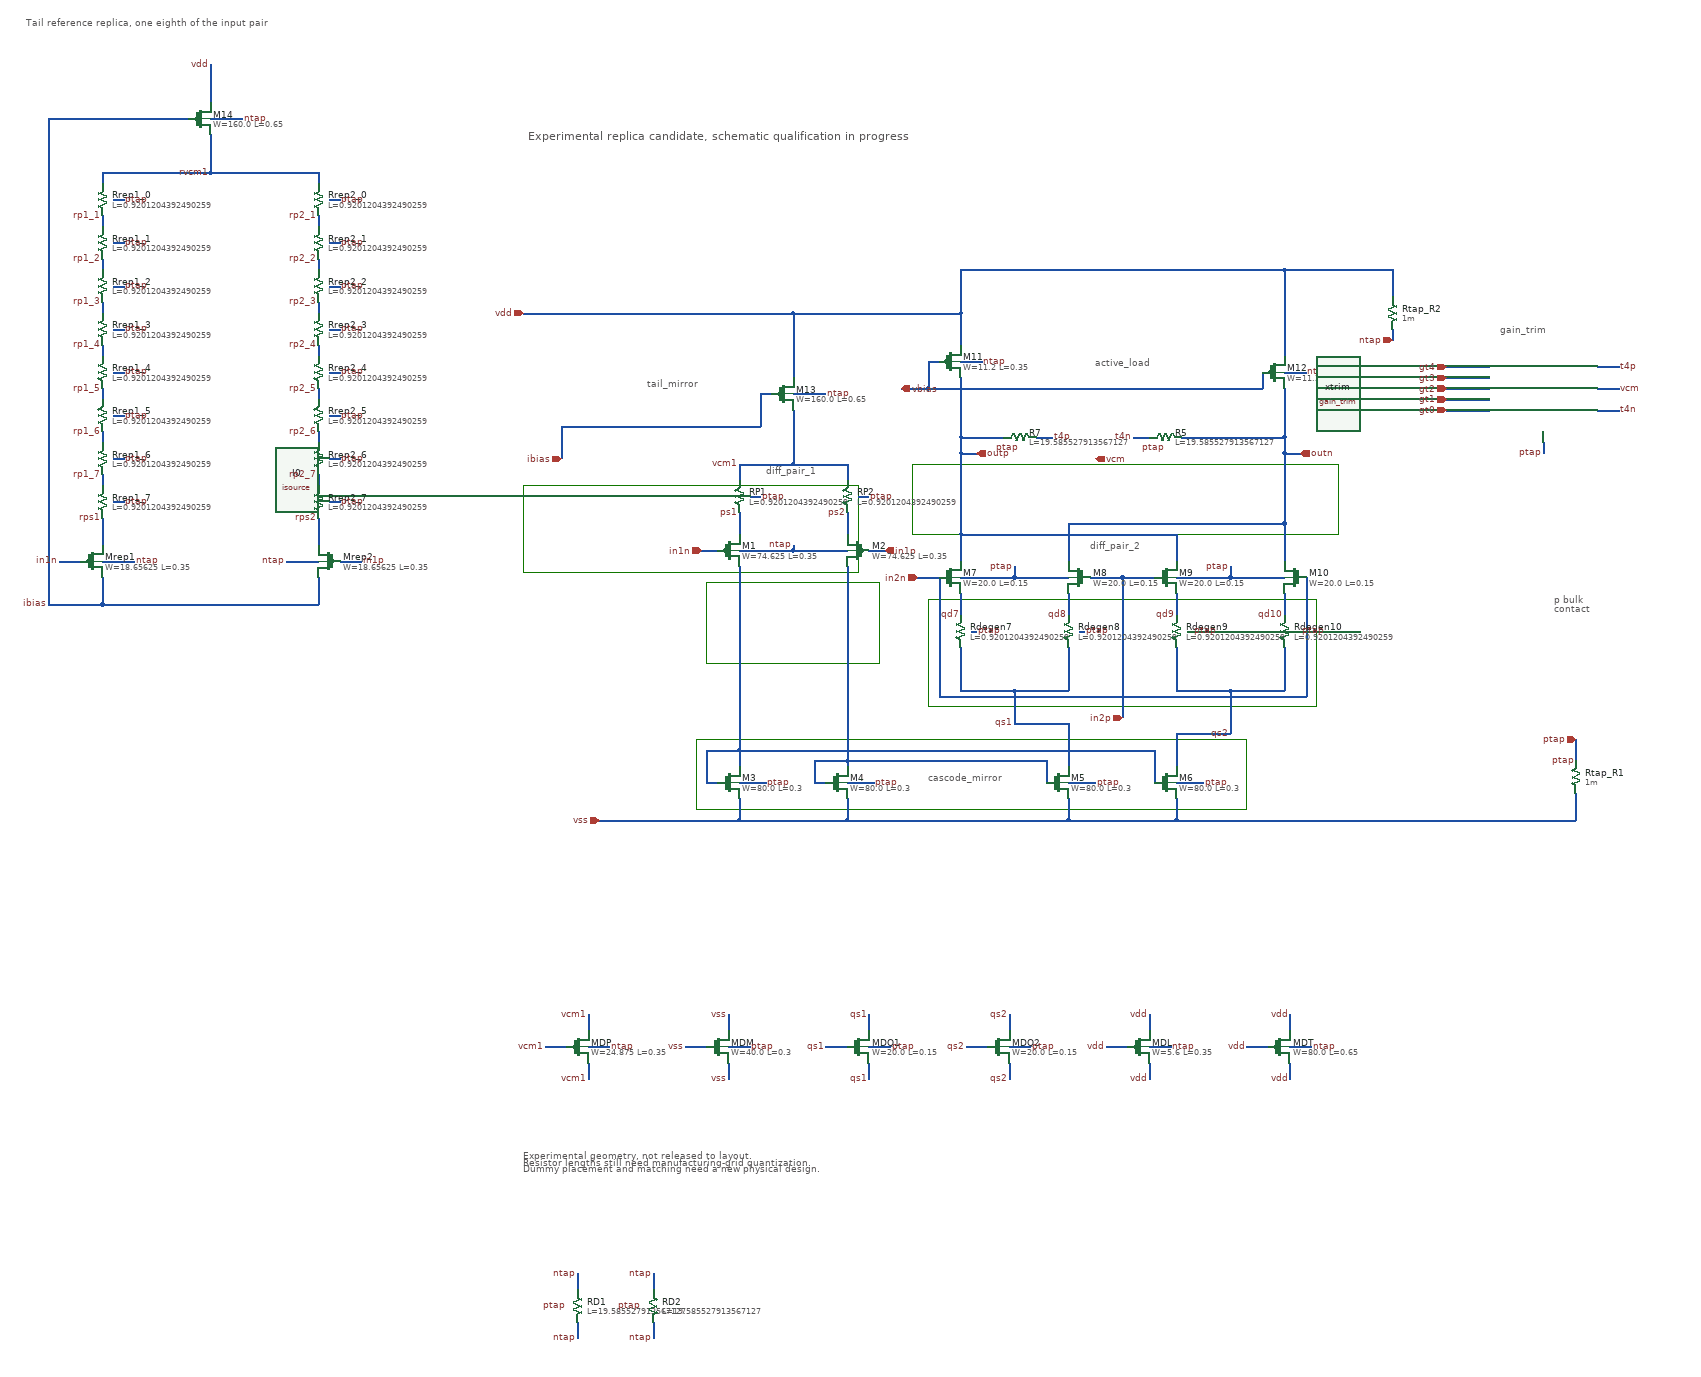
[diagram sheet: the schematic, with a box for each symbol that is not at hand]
v {xschem version=3.4.8RC file_version=1.3}
G {}
K {}
V {}
S {}
F {}
E {}
L 4 -40 -620 -40 -460 {}
L 4 -660 -460 -40 -460 {}
L 4 -660 -620 -660 -460 {}
L 4 -660 -620 -40 -620 {}
L 4 60 -660 60 -530 {}
L 4 60 -530 850 -530 {}
L 4 850 -660 850 -530 {}
L 4 60 -660 850 -660 {}
L 4 -320 -440 -320 -290 {}
L 4 -320 -290 0 -290 {}
L 4 -320 -440 0 -440 {}
L 4 -0 -440 0 -290 {}
L 4 -340 -20 680 -20 {}
L 4 -340 -150 -340 -20 {}
L 4 -340 -150 680 -150 {}
L 4 680 -150 680 -20 {}
L 4 90 -410 90 -210 {}
L 4 90 -210 810 -210 {}
L 4 810 -410 810 -210 {}
L 4 90 -410 810 -410 {}
T {p bulk
contact} 1250 -420 0 0 0.4 0.4 {}
T {tail_mirror} -430 -820 0 0 0.4 0.4 {}
T {active_load} 400 -860 0 0 0.4 0.4 {}
T {diff_pair_1} -210 -660 0 0 0.4 0.4 {}
T {cascode_mirror} 90 -90 0 0 0.4 0.4 {}
T {diff_pair_2} 390 -520 0 0 0.4 0.4 {}
T {gain_trim} 1150 -920 0 0 0.4 0.4 {}
N 450 -450 510 -450 {lab=in2p}
N 110 -450 110 -230 {lab=in2n}
N 110 -230 790 -230 {lab=in2n}
N 790 -450 790 -230 {lab=in2n}
N 150 -530 150 -480 {lab=outp}
N 550 -530 550 -480 {lab=outp}
N 150 -530 550 -530 {lab=outp}
N 350 -550 350 -480 {lab=outn}
N 350 -550 750 -550 {lab=outn}
N 450 -450 450 -190 {lab=in2p}
N 390 -450 450 -450 {lab=in2p}
N 550 -40 550 0 {lab=vss}
N 350 -40 350 0 {lab=vss}
N 350 -180 350 -100 {lab=#net1}
N 550 -160 550 -100 {lab=#net2}
N 250 -450 350 -450 {lab=ptap}
N 750 -1020 750 -860 {lab=vdd}
N 150 -940 150 -880 {lab=vdd}
N 90 -850 90 -800 {lab=vbias}
N 90 -850 110 -850 {lab=vbias}
N 90 -800 710 -800 {lab=vbias}
N 710 -830 710 -800 {lab=vbias}
N 150 -680 150 -530 {lab=outp}
N 350 0 550 0 {lab=vss}
N -60 -40 -60 0 {lab=vss}
N -260 -40 -260 0 {lab=vss}
N -260 0 -60 0 {lab=vss}
N -320 -70 -300 -70 {lab=#net3}
N -120 -70 -100 -70 {lab=#net4}
N -160 -940 -160 -820 {lab=vdd}
N -160 -940 150 -940 {lab=vdd}
N -160 -760 -160 -660 {lab=vcm1}
N -590 -940 -160 -940 {lab=vdd}
N -320 -130 -260 -130 {lab=#net3}
N -160 -500 -60 -500 {lab=ntap}
N 150 -1020 150 -940 {lab=vdd}
N 510 -130 510 -70 {lab=#net3}
N -260 -130 510 -130 {lab=#net3}
N 310 -110 310 -70 {lab=#net4}
N 750 -680 750 -550 {lab=outn}
N 750 -550 750 -480 {lab=outn}
N -160 -790 -100 -790 {lab=ntap}
N -590 -730 -590 -670 {lab=ibias}
N -220 -790 -220 -730 {lab=ibias}
N -220 -790 -200 -790 {lab=ibias}
N -590 -730 -220 -730 {lab=ibias}
N -160 -510 -160 -500 {lab=ntap}
N -260 -500 -160 -500 {lab=ntap}
N 150 -1020 750 -1020 {lab=vdd}
N -260 -70 -210 -70 {lab=ptap}
N -60 -70 -10 -70 {lab=ptap}
N 550 -70 600 -70 {lab=ptap}
N 350 -70 400 -70 {lab=ptap}
N 650 -450 750 -450 {lab=ptap}
N 650 -470 650 -450 {lab=ptap}
N 250 -470 250 -450 {lab=ptap}
N 150 -450 250 -450 {lab=ptap}
N 550 -450 650 -450 {lab=ptap}
N 1290 -150 1290 -110 {lab=ptap}
N -660 -940 -590 -940 {lab=vdd}
N 1290 -50 1290 0 {lab=vss}
N -520 0 -260 0 {lab=vss}
N -260 -130 -260 -100 {lab=#net3}
N -60 -110 -60 -100 {lab=#net4}
N 150 -680 180 -680 {lab=outp}
N 750 -680 780 -680 {lab=outn}
N 750 -830 790 -830 {lab=ntap}
N 150 -850 190 -850 {lab=ntap}
N -330 -500 -300 -500 {lab=in1n}
N -20 -500 10 -500 {lab=in1p}
N 70 -450 110 -450 {lab=in2n}
N -160 -660 -60 -660 {lab=vcm1}
N -260 -660 -160 -660 {lab=vcm1}
N 150 -240 250 -240 {lab=#net1}
N 250 -240 350 -240 {lab=#net1}
N 550 -240 650 -240 {lab=#net2}
N 650 -240 750 -240 {lab=#net2}
N 250 -180 350 -180 {lab=#net1}
N 250 -240 250 -180 {lab=#net1}
N 650 -240 650 -160 {lab=#net2}
N 550 -160 650 -160 {lab=#net2}
N -60 0 350 0 {lab=vss}
N 40 -800 90 -800 {lab=vbias}
N 150 -710 150 -680 {lab=outp}
N 150 -710 230 -710 {lab=outp}
N 150 -820 150 -710 {lab=outp}
N 750 -710 750 -680 {lab=outn}
N 550 0 1290 0 {lab=vss}
N 560 -710 750 -710 {lab=outn}
N 750 -800 750 -710 {lab=outn}
N -260 -470 -260 -130 {lab=#net3}
N -320 -130 -320 -70 {lab=#net3}
N -60 -110 310 -110 {lab=#net4}
N -60 -470 -60 -110 {lab=#net4}
N -120 -110 -60 -110 {lab=#net4}
N -120 -110 -120 -70 {lab=#net4}
N 750 -1020 950 -1020 {lab=vdd}
N 950 -1020 950 -970 {lab=vdd}
N 950 -910 950 -890 {lab=ntap}
N 290 -710 320 -710 {lab=t4p}
N 500 -710 470 -710 {lab=t4n}
N 1050 -760 1130 -760 {lab=gt0}
N 1050 -780 1130 -780 {lab=gt1}
N 1050 -800 1130 -800 {lab=gt2}
N 1050 -820 1130 -820 {lab=gt3}
N 1050 -840 1130 -840 {lab=gt4}
N 1330 -840 1370 -840 {lab=t4p}
N 1330 -800 1370 -800 {lab=vcm}
N 1330 -760 1370 -760 {lab=t4n}
N 1230 -700 1230 -680 {lab=ptap}
C {devices/title.sym} -410 90 0 0 {name=l5 author="Santiago Hofwimmer | JKU IICQC"}
C {sky130_fd_pr/nfet_01v8_lvt.sym} 330 -70 0 0 {name=M5
L=0.3
W=80.0
nf=16
ad=11.6
as=13.049999999999999
pd=84.64
ps=95.22
nrd=0.0036249999999999998
nrs=0.0036249999999999998
sa=0
sb=0
sd=0
mult=2.0
model=nfet_01v8_lvt
spiceprefix=X
}
C {sky130_fd_pr/nfet_01v8_lvt.sym} 530 -70 0 0 {name=M6
L=0.3
W=80.0
nf=16
ad=11.6
as=13.049999999999999
pd=84.64
ps=95.22
nrd=0.0036249999999999998
nrs=0.0036249999999999998
sa=0
sb=0
sd=0
mult=2.0
model=nfet_01v8_lvt
spiceprefix=X
}
C {sky130_fd_pr/nfet_01v8_lvt.sym} 130 -450 0 0 {name=M7
L=0.15
W=20.0
nf=4
ad=2.9
as=4.35
pd=21.16
ps=31.740000000000002
nrd=0.014499999999999999
nrs=0.014499999999999999
sa=0
sb=0
sd=0
mult=2.0
model=nfet_01v8_lvt
spiceprefix=X
}
C {sky130_fd_pr/nfet_01v8_lvt.sym} 530 -450 0 0 {name=M9
L=0.15
W=20.0
nf=4
ad=2.9
as=4.35
pd=21.16
ps=31.740000000000002
nrd=0.014499999999999999
nrs=0.014499999999999999
sa=0
sb=0
sd=0
mult=2.0
model=nfet_01v8_lvt
spiceprefix=X
}
C {sky130_fd_pr/nfet_01v8_lvt.sym} 770 -450 0 1 {name=M10
L=0.15
W=20.0
nf=4
ad=2.9
as=4.35
pd=21.16
ps=31.740000000000002
nrd=0.014499999999999999
nrs=0.014499999999999999
sa=0
sb=0
sd=0
mult=2.0
model=nfet_01v8_lvt
spiceprefix=X
}
C {sky130_fd_pr/nfet_01v8_lvt.sym} 370 -450 0 1 {name=M8
L=0.15
W=20.0
nf=4
ad=2.9
as=4.35
pd=21.16
ps=31.740000000000002
nrd=0.014499999999999999
nrs=0.014499999999999999
sa=0
sb=0
sd=0
mult=2.0
model=nfet_01v8_lvt
spiceprefix=X
}
C {sky130_fd_pr/pfet_01v8_lvt.sym} 130 -850 0 0 {name=M11
L=0.35
W=11.2
nf=8
ad=1.6239999999999999
as=2.03
pd=13.52
ps=16.9
nrd=0.02589285714285714
nrs=0.02589285714285714
sa=0
sb=0
sd=0
mult=2.0
model=pfet_01v8_lvt
spiceprefix=X
}
C {sky130_fd_pr/pfet_01v8_lvt.sym} 730 -830 0 0 {name=M12
L=0.35
W=11.2
nf=8
ad=1.6239999999999999
as=2.03
pd=13.52
ps=16.9
nrd=0.02589285714285714
nrs=0.02589285714285714
sa=0
sb=0
sd=0
mult=2.0
model=pfet_01v8_lvt
spiceprefix=X
}
C {iopin.sym} -660 -940 2 0 {name=p3 lab=vdd}
C {ipin.sym} -330 -500 0 0 {name=p4 lab=in1n}
C {opin.sym} 180 -680 0 0 {name=p5 lab=outp}
C {opin.sym} 780 -680 0 0 {name=p7 lab=outn}
C {iopin.sym} -520 0 2 0 {name=p9 lab=vss}
C {ipin.sym} 10 -500 0 1 {name=p10 lab=in1p}
C {ipin.sym} 70 -450 0 0 {name=p6 lab=in2n}
C {ipin.sym} 450 -190 2 0 {name=p8 lab=in2p}
C {ipin.sym} 40 -800 2 1 {name=p2 lab=vbias}
C {sky130_fd_pr/pfet_01v8_lvt.sym} -280 -500 0 0 {name=M1
L=0.35
W=74.625
nf=12
ad=10.820625
as=12.624062499999999
pd=78.105
ps=91.1225
nrd=0.0038860971524288103
nrs=0.0038860971524288103
sa=0
sb=0
sd=0
mult=2.0
model=pfet_01v8_lvt
spiceprefix=X
}
C {sky130_fd_pr/pfet_01v8_lvt.sym} -180 -790 0 0 {name=M13
L=0.65
W=160.0
nf=16
ad=23.2
as=26.099999999999998
pd=164.64
ps=185.21999999999997
nrd=0.0018124999999999999
nrs=0.0018124999999999999
sa=0
sb=0
sd=0
mult=16.0
model=pfet_01v8_lvt
spiceprefix=X
}
C {sky130_fd_pr/nfet_01v8_lvt.sym} -280 -70 0 0 {name=M3
L=0.3
W=80.0
nf=16
ad=11.6
as=13.049999999999999
pd=84.64
ps=95.22
nrd=0.0036249999999999998
nrs=0.0036249999999999998
sa=0
sb=0
sd=0
mult=2.0
model=nfet_01v8_lvt
spiceprefix=X
}
C {sky130_fd_pr/nfet_01v8_lvt.sym} -80 -70 0 0 {name=M4
L=0.3
W=80.0
nf=16
ad=11.6
as=13.049999999999999
pd=84.64
ps=95.22
nrd=0.0036249999999999998
nrs=0.0036249999999999998
sa=0
sb=0
sd=0
mult=2.0
model=nfet_01v8_lvt
spiceprefix=X
}
C {sky130_fd_pr/pfet_01v8_lvt.sym} -40 -500 0 1 {name=M2
L=0.35
W=74.625
nf=12
ad=10.820625
as=12.624062499999999
pd=78.105
ps=91.1225
nrd=0.0038860971524288103
nrs=0.0038860971524288103
sa=0
sb=0
sd=0
mult=2.0
model=pfet_01v8_lvt
spiceprefix=X
}

C {ipin.sym} -590 -670 3 0 {name=p11 lab=ibias}

C {lab_pin.sym} -100 -790 2 0 {name=p14 sig_type=std_logic lab=ntap}
C {lab_pin.sym} 190 -850 2 0 {name=p15 sig_type=std_logic lab=ntap}
C {lab_pin.sym} 790 -830 2 0 {name=p16 sig_type=std_logic lab=ntap}
C {lab_pin.sym} -160 -510 1 0 {name=p17 sig_type=std_logic lab=ntap}
C {lab_pin.sym} -210 -70 2 0 {name=p21 sig_type=std_logic lab=ptap}
C {lab_pin.sym} -10 -70 2 0 {name=p22 sig_type=std_logic lab=ptap}
C {lab_pin.sym} 400 -70 2 0 {name=p23 sig_type=std_logic lab=ptap}
C {lab_pin.sym} 600 -70 2 0 {name=p24 sig_type=std_logic lab=ptap}
C {lab_pin.sym} 650 -470 1 0 {name=p25 sig_type=std_logic lab=ptap}
C {lab_pin.sym} 250 -470 1 0 {name=p26 sig_type=std_logic lab=ptap}
C {devices/res.sym} 1290 -80 2 0 {name=Rtap_R1
value=1m
m=1
}
C {lab_pin.sym} 1290 -110 2 1 {name=p29 sig_type=std_logic lab=ptap}







C {sky130_fd_pr/res_high_po_5p73.sym} 260 -710 3 0 {name=R7
L=19.585527913567127
mult=2.0
model=res_high_po_5p73
spiceprefix=X
}
C {iopin.sym} 1290 -150 3 0 {name=p31 lab=ptap}
C {sky130_fd_pr/res_high_po_5p73.sym} 530 -710 3 0 {name=R5
L=19.585527913567127
mult=2.0
model=res_high_po_5p73
spiceprefix=X
}
C {opin.sym} 400 -670 0 0 {name=p33 lab=vcm}
C {isource.sym} -590 -140 0 0 {name=I0 value=5u
spice_ignore=true}
C {lab_pin.sym} -260 -660 0 0 {name=p1 sig_type=std_logic lab=vcm1}
C {devices/res.sym} 950 -940 0 0 {name=Rtap_R2
value=1m
m=1
}
C {iopin.sym} 950 -890 1 0 {name=p12 lab=ntap}
C {lab_pin.sym} 320 -710 2 0 {name=lt1 sig_type=std_logic lab=t4p}
C {lab_pin.sym} 470 -710 0 0 {name=lt2 sig_type=std_logic lab=t4n}
C {lit_compac_sky/verification/porting/sky_replica_schematic/schematic/gain_trim.sym} 1150 -720 0 0 {name=xtrim}
C {ipin.sym} 1050 -760 0 0 {name=pgt0 lab=gt0}
C {ipin.sym} 1050 -780 0 0 {name=pgt1 lab=gt1}
C {ipin.sym} 1050 -800 0 0 {name=pgt2 lab=gt2}
C {ipin.sym} 1050 -820 0 0 {name=pgt3 lab=gt3}
C {ipin.sym} 1050 -840 0 0 {name=pgt4 lab=gt4}
C {lab_pin.sym} 1370 -840 2 0 {name=lt3 sig_type=std_logic lab=t4p}
C {lab_pin.sym} 1370 -800 2 0 {name=lt4 sig_type=std_logic lab=vcm}
C {lab_pin.sym} 1370 -760 2 0 {name=lt5 sig_type=std_logic lab=t4n}
C {lab_pin.sym} 1230 -680 3 0 {name=lt6 sig_type=std_logic lab=ptap}
C {lab_pin.sym} 250 -180 3 0 {name=pdm1 sig_type=std_logic lab=qs1}
C {lab_pin.sym} 650 -160 3 0 {name=pdm2 sig_type=std_logic lab=qs2}
C {sky130_fd_pr/pfet_01v8_lvt.sym} -560 420 0 0 {name=MDP
L=0.35
W=24.875
nf=4
ad=3.6068749999999996
as=5.4103125
pd=26.035
ps=39.0525
nrd=0.011658291457286432
nrs=0.011658291457286432
sa=0
sb=0
sd=0
mult=2.0
model=pfet_01v8_lvt
spiceprefix=X
}
N -540 390 -540 360 {lab=vcm1}
C {lab_pin.sym} -540 360 1 0 {name=pdm3 sig_type=std_logic lab=vcm1}
N -540 450 -540 480 {lab=vcm1}
C {lab_pin.sym} -540 480 3 0 {name=pdm4 sig_type=std_logic lab=vcm1}
N -580 420 -620 420 {lab=vcm1}
C {lab_pin.sym} -620 420 0 0 {name=pdm5 sig_type=std_logic lab=vcm1}
N -540 420 -500 420 {lab=ntap}
C {lab_pin.sym} -500 420 2 0 {name=pdm6 sig_type=std_logic lab=ntap}
C {sky130_fd_pr/nfet_01v8_lvt.sym} -300 420 0 0 {name=MDM
L=0.3
W=40.0
nf=8
ad=5.8
as=7.249999999999999
pd=42.32
ps=52.9
nrd=0.0072499999999999995
nrs=0.0072499999999999995
sa=0
sb=0
sd=0
mult=2.0
model=nfet_01v8_lvt
spiceprefix=X
}
N -280 390 -280 360 {lab=vss}
C {lab_pin.sym} -280 360 1 0 {name=pdm7 sig_type=std_logic lab=vss}
N -280 450 -280 480 {lab=vss}
C {lab_pin.sym} -280 480 3 0 {name=pdm8 sig_type=std_logic lab=vss}
N -320 420 -360 420 {lab=vss}
C {lab_pin.sym} -360 420 0 0 {name=pdm9 sig_type=std_logic lab=vss}
N -280 420 -240 420 {lab=ptap}
C {lab_pin.sym} -240 420 2 0 {name=pdm10 sig_type=std_logic lab=ptap}
C {sky130_fd_pr/nfet_01v8_lvt.sym} -40 420 0 0 {name=MDQ1
L=0.15
W=20.0
nf=4
ad=2.9
as=4.35
pd=21.16
ps=31.740000000000002
nrd=0.014499999999999999
nrs=0.014499999999999999
sa=0
sb=0
sd=0
mult=2.0
model=nfet_01v8_lvt
spiceprefix=X
}
N -20 390 -20 360 {lab=qs1}
C {lab_pin.sym} -20 360 1 0 {name=pdm11 sig_type=std_logic lab=qs1}
N -20 450 -20 480 {lab=qs1}
C {lab_pin.sym} -20 480 3 0 {name=pdm12 sig_type=std_logic lab=qs1}
N -60 420 -100 420 {lab=qs1}
C {lab_pin.sym} -100 420 0 0 {name=pdm13 sig_type=std_logic lab=qs1}
N -20 420 20 420 {lab=ptap}
C {lab_pin.sym} 20 420 2 0 {name=pdm14 sig_type=std_logic lab=ptap}
C {sky130_fd_pr/nfet_01v8_lvt.sym} 220 420 0 0 {name=MDQ2
L=0.15
W=20.0
nf=4
ad=2.9
as=4.35
pd=21.16
ps=31.740000000000002
nrd=0.014499999999999999
nrs=0.014499999999999999
sa=0
sb=0
sd=0
mult=2.0
model=nfet_01v8_lvt
spiceprefix=X
}
N 240 390 240 360 {lab=qs2}
C {lab_pin.sym} 240 360 1 0 {name=pdm15 sig_type=std_logic lab=qs2}
N 240 450 240 480 {lab=qs2}
C {lab_pin.sym} 240 480 3 0 {name=pdm16 sig_type=std_logic lab=qs2}
N 200 420 160 420 {lab=qs2}
C {lab_pin.sym} 160 420 0 0 {name=pdm17 sig_type=std_logic lab=qs2}
N 240 420 280 420 {lab=ptap}
C {lab_pin.sym} 280 420 2 0 {name=pdm18 sig_type=std_logic lab=ptap}
C {sky130_fd_pr/pfet_01v8_lvt.sym} 480 420 0 0 {name=MDL
L=0.35
W=5.6
nf=4
ad=0.8119999999999999
as=1.2179999999999997
pd=6.76
ps=10.14
nrd=0.05178571428571428
nrs=0.05178571428571428
sa=0
sb=0
sd=0
mult=2.0
model=pfet_01v8_lvt
spiceprefix=X
}
N 500 390 500 360 {lab=vdd}
C {lab_pin.sym} 500 360 1 0 {name=pdm19 sig_type=std_logic lab=vdd}
N 500 450 500 480 {lab=vdd}
C {lab_pin.sym} 500 480 3 0 {name=pdm20 sig_type=std_logic lab=vdd}
N 460 420 420 420 {lab=vdd}
C {lab_pin.sym} 420 420 0 0 {name=pdm21 sig_type=std_logic lab=vdd}
N 500 420 540 420 {lab=ntap}
C {lab_pin.sym} 540 420 2 0 {name=pdm22 sig_type=std_logic lab=ntap}
C {sky130_fd_pr/pfet_01v8_lvt.sym} 740 420 0 0 {name=MDT
L=0.65
W=80.0
nf=8
ad=11.6
as=14.499999999999998
pd=82.32
ps=102.89999999999999
nrd=0.0036249999999999998
nrs=0.0036249999999999998
sa=0
sb=0
sd=0
mult=2.0
model=pfet_01v8_lvt
spiceprefix=X
}
N 760 390 760 360 {lab=vdd}
C {lab_pin.sym} 760 360 1 0 {name=pdm23 sig_type=std_logic lab=vdd}
N 760 450 760 480 {lab=vdd}
C {lab_pin.sym} 760 480 3 0 {name=pdm24 sig_type=std_logic lab=vdd}
N 720 420 680 420 {lab=vdd}
C {lab_pin.sym} 680 420 0 0 {name=pdm25 sig_type=std_logic lab=vdd}
N 760 420 800 420 {lab=ntap}
C {lab_pin.sym} 800 420 2 0 {name=pdm26 sig_type=std_logic lab=ntap}


C {sky130_fd_pr/res_high_po_5p73.sym} -560 900 0 0 {name=RD1
L=19.585527913567127
mult=2.0
model=res_high_po_5p73
spiceprefix=X
}
N -560 870 -560 840 {lab=ntap}
C {lab_pin.sym} -560 840 1 0 {name=pdm101 sig_type=std_logic lab=ntap}
N -560 930 -560 960 {lab=ntap}
C {lab_pin.sym} -560 960 3 0 {name=pdm102 sig_type=std_logic lab=ntap}
C {sky130_fd_pr/res_high_po_5p73.sym} -420 900 0 0 {name=RD2
L=19.585527913567127
mult=2.0
model=res_high_po_5p73
spiceprefix=X
}
N -420 870 -420 840 {lab=ntap}
C {lab_pin.sym} -420 840 1 0 {name=pdm103 sig_type=std_logic lab=ntap}
N -420 930 -420 960 {lab=ntap}
C {lab_pin.sym} -420 960 3 0 {name=pdm104 sig_type=std_logic lab=ntap}
C {devices/lab_pin.sym} -440 900 0 0 {name=body_RD2 lab=ptap}
C {devices/lab_pin.sym} -580 900 0 0 {name=body_RD1 lab=ptap}
C {devices/lab_pin.sym} 530 -690 0 0 {name=body_R5 lab=ptap}
C {devices/lab_pin.sym} 260 -690 0 0 {name=body_R7 lab=ptap}
T {Experimental geometry, not released to layout.
Resistor lengths still need manufacturing-grid quantization.
Dummy placement and matching need a new physical design.} -660 610 0 0 0.3 0.3 {}
C {sky130_fd_pr/res_high_po_5p73.sym} -260 -600 2 0 {name=RP1
L=0.9201204392490259
mult=2
model=res_high_po_5p73
spiceprefix=X
}
N -260 -660 -260 -630 {}
N -260 -570 -260 -530 {}
C {devices/lab_pin.sym} -260 -570 1 0 {name=candidate_label1 sig_type=std_logic lab=ps1}
N -240 -600 -220 -600 {}
C {devices/lab_pin.sym} -220 -600 0 1 {name=candidate_label2 sig_type=std_logic lab=ptap}
C {sky130_fd_pr/res_high_po_5p73.sym} -60 -600 2 0 {name=RP2
L=0.9201204392490259
mult=2
model=res_high_po_5p73
spiceprefix=X
}
N -60 -660 -60 -630 {}
N -60 -570 -60 -530 {}
C {devices/lab_pin.sym} -60 -570 1 0 {name=candidate_label3 sig_type=std_logic lab=ps2}
N -40 -600 -20 -600 {}
C {devices/lab_pin.sym} -20 -600 0 1 {name=candidate_label4 sig_type=std_logic lab=ptap}
C {sky130_fd_pr/res_high_po_5p73.sym} 150 -350 2 0 {name=Rdegen7
L=0.9201204392490259
mult=2
model=res_high_po_5p73
spiceprefix=X
}
N 150 -420 150 -380 {}
N 150 -320 150 -240 {}
C {devices/lab_pin.sym} 150 -380 1 0 {name=candidate_label5 sig_type=std_logic lab=qd7}
N 170 -350 180 -350 {}
C {devices/lab_pin.sym} 180 -350 0 1 {name=candidate_label6 sig_type=std_logic lab=ptap}
C {sky130_fd_pr/res_high_po_5p73.sym} 350 -350 2 0 {name=Rdegen8
L=0.9201204392490259
mult=2
model=res_high_po_5p73
spiceprefix=X
}
N 350 -420 350 -380 {}
N 350 -320 350 -240 {}
C {devices/lab_pin.sym} 350 -380 1 0 {name=candidate_label7 sig_type=std_logic lab=qd8}
N 370 -350 380 -350 {}
C {devices/lab_pin.sym} 380 -350 0 1 {name=candidate_label8 sig_type=std_logic lab=ptap}
C {sky130_fd_pr/res_high_po_5p73.sym} 550 -350 2 0 {name=Rdegen9
L=0.9201204392490259
mult=2
model=res_high_po_5p73
spiceprefix=X
}
N 550 -420 550 -380 {}
N 550 -320 550 -240 {}
C {devices/lab_pin.sym} 550 -380 1 0 {name=candidate_label9 sig_type=std_logic lab=qd9}
N 570 -350 580 -350 {}
C {devices/lab_pin.sym} 580 -350 0 1 {name=candidate_label10 sig_type=std_logic lab=ptap}
C {sky130_fd_pr/res_high_po_5p73.sym} 750 -350 2 0 {name=Rdegen10
L=0.9201204392490259
mult=2
model=res_high_po_5p73
spiceprefix=X
}
N 750 -420 750 -380 {}
N 750 -320 750 -240 {}
C {devices/lab_pin.sym} 750 -380 1 0 {name=candidate_label11 sig_type=std_logic lab=qd10}
N 770 -350 780 -350 {}
C {devices/lab_pin.sym} 780 -350 0 1 {name=candidate_label12 sig_type=std_logic lab=ptap}
T {Tail reference replica, one eighth of the input pair} -1580 -1490 0 0 0.4 0.4 {}
C {sky130_fd_pr/pfet_01v8_lvt.sym} -1260 -1300 0 0 {name=M14
L=0.65
W=160.0
nf=16
ad=23.2
as=26.099999999999998
pd=164.64
ps=185.21999999999997
nrd=0.0018124999999999999
nrs=0.0018124999999999999
sa=0
sb=0
sd=0
mult=2.0
model=pfet_01v8_lvt
spiceprefix=X
}
N -1240 -1330 -1240 -1400 {}
C {devices/lab_pin.sym} -1240 -1400 1 0 {name=candidate_label13 sig_type=std_logic lab=vdd}
N -1240 -1300 -1180 -1300 {}
C {devices/lab_pin.sym} -1180 -1300 0 1 {name=candidate_label14 sig_type=std_logic lab=ntap}
N -1280 -1300 -1540 -1300 {}
N -1540 -1300 -1540 -400 {}
N -1240 -1270 -1240 -1200 {}
C {devices/lab_pin.sym} -1240 -1200 1 0 {name=candidate_label15 sig_type=std_logic lab=rvcm1}
N -1440 -1200 -1240 -1200 {}
N -1240 -1200 -1040 -1200 {}
C {sky130_fd_pr/res_high_po_5p73.sym} -1440 -1150 2 0 {name=Rrep1_0
L=0.9201204392490259
mult=2
model=res_high_po_5p73
spiceprefix=X
}
N -1440 -1180 -1440 -1200 {}
N -1420 -1150 -1400 -1150 {}
C {devices/lab_pin.sym} -1400 -1150 0 1 {name=candidate_label16 sig_type=std_logic lab=ptap}
C {sky130_fd_pr/res_high_po_5p73.sym} -1440 -1070 2 0 {name=Rrep1_1
L=0.9201204392490259
mult=2
model=res_high_po_5p73
spiceprefix=X
}
N -1440 -1100 -1440 -1120 {}
C {devices/lab_pin.sym} -1440 -1120 1 0 {name=candidate_label17 sig_type=std_logic lab=rp1_1}
N -1420 -1070 -1400 -1070 {}
C {devices/lab_pin.sym} -1400 -1070 0 1 {name=candidate_label18 sig_type=std_logic lab=ptap}
C {sky130_fd_pr/res_high_po_5p73.sym} -1440 -990 2 0 {name=Rrep1_2
L=0.9201204392490259
mult=2
model=res_high_po_5p73
spiceprefix=X
}
N -1440 -1020 -1440 -1040 {}
C {devices/lab_pin.sym} -1440 -1040 1 0 {name=candidate_label19 sig_type=std_logic lab=rp1_2}
N -1420 -990 -1400 -990 {}
C {devices/lab_pin.sym} -1400 -990 0 1 {name=candidate_label20 sig_type=std_logic lab=ptap}
C {sky130_fd_pr/res_high_po_5p73.sym} -1440 -910 2 0 {name=Rrep1_3
L=0.9201204392490259
mult=2
model=res_high_po_5p73
spiceprefix=X
}
N -1440 -940 -1440 -960 {}
C {devices/lab_pin.sym} -1440 -960 1 0 {name=candidate_label21 sig_type=std_logic lab=rp1_3}
N -1420 -910 -1400 -910 {}
C {devices/lab_pin.sym} -1400 -910 0 1 {name=candidate_label22 sig_type=std_logic lab=ptap}
C {sky130_fd_pr/res_high_po_5p73.sym} -1440 -830 2 0 {name=Rrep1_4
L=0.9201204392490259
mult=2
model=res_high_po_5p73
spiceprefix=X
}
N -1440 -860 -1440 -880 {}
C {devices/lab_pin.sym} -1440 -880 1 0 {name=candidate_label23 sig_type=std_logic lab=rp1_4}
N -1420 -830 -1400 -830 {}
C {devices/lab_pin.sym} -1400 -830 0 1 {name=candidate_label24 sig_type=std_logic lab=ptap}
C {sky130_fd_pr/res_high_po_5p73.sym} -1440 -750 2 0 {name=Rrep1_5
L=0.9201204392490259
mult=2
model=res_high_po_5p73
spiceprefix=X
}
N -1440 -780 -1440 -800 {}
C {devices/lab_pin.sym} -1440 -800 1 0 {name=candidate_label25 sig_type=std_logic lab=rp1_5}
N -1420 -750 -1400 -750 {}
C {devices/lab_pin.sym} -1400 -750 0 1 {name=candidate_label26 sig_type=std_logic lab=ptap}
C {sky130_fd_pr/res_high_po_5p73.sym} -1440 -670 2 0 {name=Rrep1_6
L=0.9201204392490259
mult=2
model=res_high_po_5p73
spiceprefix=X
}
N -1440 -700 -1440 -720 {}
C {devices/lab_pin.sym} -1440 -720 1 0 {name=candidate_label27 sig_type=std_logic lab=rp1_6}
N -1420 -670 -1400 -670 {}
C {devices/lab_pin.sym} -1400 -670 0 1 {name=candidate_label28 sig_type=std_logic lab=ptap}
C {sky130_fd_pr/res_high_po_5p73.sym} -1440 -590 2 0 {name=Rrep1_7
L=0.9201204392490259
mult=2
model=res_high_po_5p73
spiceprefix=X
}
N -1440 -620 -1440 -640 {}
C {devices/lab_pin.sym} -1440 -640 1 0 {name=candidate_label29 sig_type=std_logic lab=rp1_7}
N -1420 -590 -1400 -590 {}
C {devices/lab_pin.sym} -1400 -590 0 1 {name=candidate_label30 sig_type=std_logic lab=ptap}
N -1440 -560 -1440 -510 {}
C {devices/lab_pin.sym} -1440 -560 1 0 {name=candidate_label31 sig_type=std_logic lab=rps1}
C {sky130_fd_pr/pfet_01v8_lvt.sym} -1460 -480 0 0 {name=Mrep1
L=0.35
W=18.65625
nf=3
ad=3.6068749999999996
as=3.6068749999999996
pd=26.035
ps=26.035
nrd=0.015544388609715241
nrs=0.015544388609715241
sa=0
sb=0
sd=0
mult=1
model=pfet_01v8_lvt
spiceprefix=X
}
N -1480 -480 -1520 -480 {}
C {devices/lab_pin.sym} -1520 -480 0 0 {name=candidate_label32 sig_type=std_logic lab=in1n}
N -1440 -480 -1380 -480 {}
C {devices/lab_pin.sym} -1380 -480 0 1 {name=candidate_label33 sig_type=std_logic lab=ntap}
N -1440 -450 -1440 -400 {}
C {sky130_fd_pr/res_high_po_5p73.sym} -1040 -1150 2 0 {name=Rrep2_0
L=0.9201204392490259
mult=2
model=res_high_po_5p73
spiceprefix=X
}
N -1040 -1180 -1040 -1200 {}
N -1020 -1150 -1000 -1150 {}
C {devices/lab_pin.sym} -1000 -1150 0 1 {name=candidate_label34 sig_type=std_logic lab=ptap}
C {sky130_fd_pr/res_high_po_5p73.sym} -1040 -1070 2 0 {name=Rrep2_1
L=0.9201204392490259
mult=2
model=res_high_po_5p73
spiceprefix=X
}
N -1040 -1100 -1040 -1120 {}
C {devices/lab_pin.sym} -1040 -1120 1 0 {name=candidate_label35 sig_type=std_logic lab=rp2_1}
N -1020 -1070 -1000 -1070 {}
C {devices/lab_pin.sym} -1000 -1070 0 1 {name=candidate_label36 sig_type=std_logic lab=ptap}
C {sky130_fd_pr/res_high_po_5p73.sym} -1040 -990 2 0 {name=Rrep2_2
L=0.9201204392490259
mult=2
model=res_high_po_5p73
spiceprefix=X
}
N -1040 -1020 -1040 -1040 {}
C {devices/lab_pin.sym} -1040 -1040 1 0 {name=candidate_label37 sig_type=std_logic lab=rp2_2}
N -1020 -990 -1000 -990 {}
C {devices/lab_pin.sym} -1000 -990 0 1 {name=candidate_label38 sig_type=std_logic lab=ptap}
C {sky130_fd_pr/res_high_po_5p73.sym} -1040 -910 2 0 {name=Rrep2_3
L=0.9201204392490259
mult=2
model=res_high_po_5p73
spiceprefix=X
}
N -1040 -940 -1040 -960 {}
C {devices/lab_pin.sym} -1040 -960 1 0 {name=candidate_label39 sig_type=std_logic lab=rp2_3}
N -1020 -910 -1000 -910 {}
C {devices/lab_pin.sym} -1000 -910 0 1 {name=candidate_label40 sig_type=std_logic lab=ptap}
C {sky130_fd_pr/res_high_po_5p73.sym} -1040 -830 2 0 {name=Rrep2_4
L=0.9201204392490259
mult=2
model=res_high_po_5p73
spiceprefix=X
}
N -1040 -860 -1040 -880 {}
C {devices/lab_pin.sym} -1040 -880 1 0 {name=candidate_label41 sig_type=std_logic lab=rp2_4}
N -1020 -830 -1000 -830 {}
C {devices/lab_pin.sym} -1000 -830 0 1 {name=candidate_label42 sig_type=std_logic lab=ptap}
C {sky130_fd_pr/res_high_po_5p73.sym} -1040 -750 2 0 {name=Rrep2_5
L=0.9201204392490259
mult=2
model=res_high_po_5p73
spiceprefix=X
}
N -1040 -780 -1040 -800 {}
C {devices/lab_pin.sym} -1040 -800 1 0 {name=candidate_label43 sig_type=std_logic lab=rp2_5}
N -1020 -750 -1000 -750 {}
C {devices/lab_pin.sym} -1000 -750 0 1 {name=candidate_label44 sig_type=std_logic lab=ptap}
C {sky130_fd_pr/res_high_po_5p73.sym} -1040 -670 2 0 {name=Rrep2_6
L=0.9201204392490259
mult=2
model=res_high_po_5p73
spiceprefix=X
}
N -1040 -700 -1040 -720 {}
C {devices/lab_pin.sym} -1040 -720 1 0 {name=candidate_label45 sig_type=std_logic lab=rp2_6}
N -1020 -670 -1000 -670 {}
C {devices/lab_pin.sym} -1000 -670 0 1 {name=candidate_label46 sig_type=std_logic lab=ptap}
C {sky130_fd_pr/res_high_po_5p73.sym} -1040 -590 2 0 {name=Rrep2_7
L=0.9201204392490259
mult=2
model=res_high_po_5p73
spiceprefix=X
}
N -1040 -620 -1040 -640 {}
C {devices/lab_pin.sym} -1040 -640 1 0 {name=candidate_label47 sig_type=std_logic lab=rp2_7}
N -1020 -590 -1000 -590 {}
C {devices/lab_pin.sym} -1000 -590 0 1 {name=candidate_label48 sig_type=std_logic lab=ptap}
N -1040 -560 -1040 -510 {}
C {devices/lab_pin.sym} -1040 -560 1 0 {name=candidate_label49 sig_type=std_logic lab=rps2}
C {sky130_fd_pr/pfet_01v8_lvt.sym} -1020 -480 0 1 {name=Mrep2
L=0.35
W=18.65625
nf=3
ad=3.6068749999999996
as=3.6068749999999996
pd=26.035
ps=26.035
nrd=0.015544388609715241
nrs=0.015544388609715241
sa=0
sb=0
sd=0
mult=1
model=pfet_01v8_lvt
spiceprefix=X
}
N -1000 -480 -960 -480 {}
C {devices/lab_pin.sym} -960 -480 0 1 {name=candidate_label50 sig_type=std_logic lab=in1p}
N -1040 -480 -1100 -480 {}
C {devices/lab_pin.sym} -1100 -480 0 0 {name=candidate_label51 sig_type=std_logic lab=ntap}
N -1040 -450 -1040 -400 {}
N -1540 -400 -1440 -400 {}
N -1440 -400 -1040 -400 {}
C {devices/lab_pin.sym} -1540 -400 0 0 {name=candidate_label52 sig_type=std_logic lab=ibias}
T {Experimental replica candidate, schematic qualification in progress} -650 -1280 0 0 0.6 0.6 {}
